VERSION 5.8 ;
BUSBITCHARS "[]" ;
DIVIDERCHAR "/" ;
UNITS
    DATABASE MICRONS 1000 ;
END UNITS

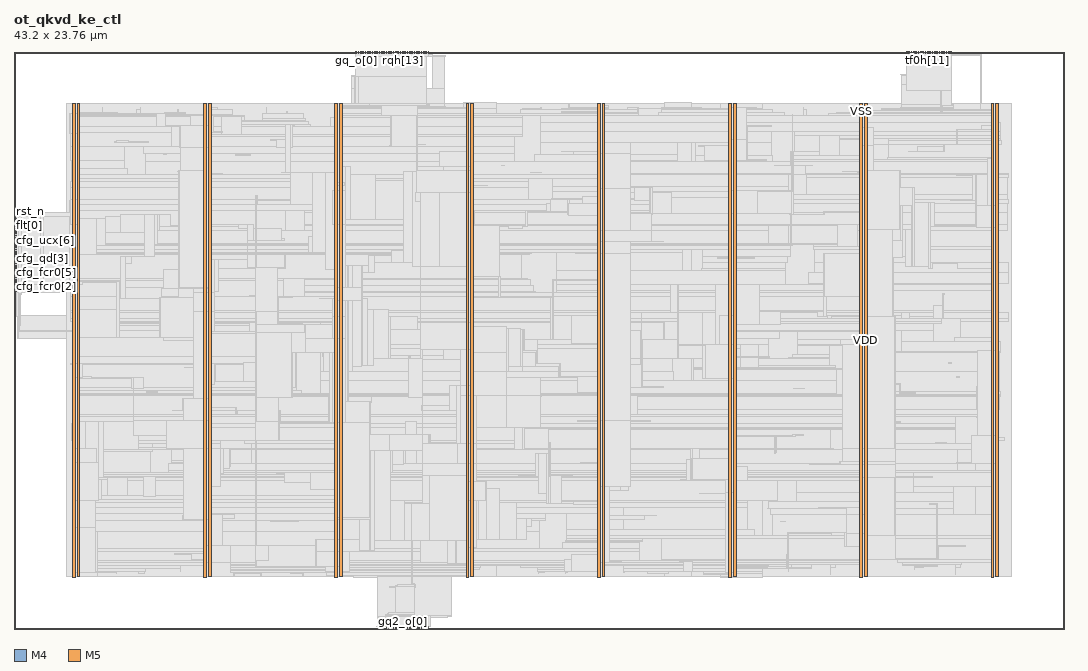
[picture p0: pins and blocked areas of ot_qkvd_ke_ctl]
MACRO ot_qkvd_ke_ctl
  FOREIGN ot_qkvd_ke_ctl 0 0 ;
  CLASS BLOCK ;
  SIZE 43.2 BY 23.76 ;
  PIN cfg_fcr0[0]
    DIRECTION INPUT ;
    USE SIGNAL ;
    PORT
      LAYER M4 ;
        RECT  0 13.872 0.084 13.896 ;
    END
  END cfg_fcr0[0]
  PIN cfg_fcr0[1]
    DIRECTION INPUT ;
    USE SIGNAL ;
    PORT
      LAYER M4 ;
        RECT  0 13.968 0.084 13.992 ;
    END
  END cfg_fcr0[1]
  PIN cfg_fcr0[2]
    DIRECTION INPUT ;
    USE SIGNAL ;
    PORT
      LAYER M4 ;
        RECT  0 14.064 0.084 14.088 ;
    END
  END cfg_fcr0[2]
  PIN cfg_fcr0[3]
    DIRECTION INPUT ;
    USE SIGNAL ;
    PORT
      LAYER M4 ;
        RECT  0 14.16 0.084 14.184 ;
    END
  END cfg_fcr0[3]
  PIN cfg_fcr0[4]
    DIRECTION INPUT ;
    USE SIGNAL ;
    PORT
      LAYER M4 ;
        RECT  0 14.256 0.084 14.28 ;
    END
  END cfg_fcr0[4]
  PIN cfg_fcr0[5]
    DIRECTION INPUT ;
    USE SIGNAL ;
    PORT
      LAYER M4 ;
        RECT  0 14.352 0.084 14.376 ;
    END
  END cfg_fcr0[5]
  PIN cfg_fcr0[6]
    DIRECTION INPUT ;
    USE SIGNAL ;
    PORT
      LAYER M4 ;
        RECT  0 14.448 0.084 14.472 ;
    END
  END cfg_fcr0[6]
  PIN cfg_fcr0[7]
    DIRECTION INPUT ;
    USE SIGNAL ;
    PORT
      LAYER M4 ;
        RECT  0 14.544 0.084 14.568 ;
    END
  END cfg_fcr0[7]
  PIN cfg_qd[0]
    DIRECTION INPUT ;
    USE SIGNAL ;
    PORT
      LAYER M4 ;
        RECT  0 14.64 0.084 14.664 ;
    END
  END cfg_qd[0]
  PIN cfg_qd[1]
    DIRECTION INPUT ;
    USE SIGNAL ;
    PORT
      LAYER M4 ;
        RECT  0 14.736 0.084 14.76 ;
    END
  END cfg_qd[1]
  PIN cfg_qd[2]
    DIRECTION INPUT ;
    USE SIGNAL ;
    PORT
      LAYER M4 ;
        RECT  0 14.832 0.084 14.856 ;
    END
  END cfg_qd[2]
  PIN cfg_qd[3]
    DIRECTION INPUT ;
    USE SIGNAL ;
    PORT
      LAYER M4 ;
        RECT  0 14.928 0.084 14.952 ;
    END
  END cfg_qd[3]
  PIN cfg_qd[4]
    DIRECTION INPUT ;
    USE SIGNAL ;
    PORT
      LAYER M4 ;
        RECT  0 15.024 0.084 15.048 ;
    END
  END cfg_qd[4]
  PIN cfg_qd[5]
    DIRECTION INPUT ;
    USE SIGNAL ;
    PORT
      LAYER M4 ;
        RECT  0 15.12 0.084 15.144 ;
    END
  END cfg_qd[5]
  PIN cfg_qd[6]
    DIRECTION INPUT ;
    USE SIGNAL ;
    PORT
      LAYER M4 ;
        RECT  0 15.216 0.084 15.24 ;
    END
  END cfg_qd[6]
  PIN cfg_qd[7]
    DIRECTION INPUT ;
    USE SIGNAL ;
    PORT
      LAYER M4 ;
        RECT  0 15.312 0.084 15.336 ;
    END
  END cfg_qd[7]
  PIN cfg_ucx[0]
    DIRECTION INPUT ;
    USE SIGNAL ;
    PORT
      LAYER M4 ;
        RECT  0 15.408 0.084 15.432 ;
    END
  END cfg_ucx[0]
  PIN cfg_ucx[1]
    DIRECTION INPUT ;
    USE SIGNAL ;
    PORT
      LAYER M4 ;
        RECT  0 15.504 0.084 15.528 ;
    END
  END cfg_ucx[1]
  PIN cfg_ucx[2]
    DIRECTION INPUT ;
    USE SIGNAL ;
    PORT
      LAYER M4 ;
        RECT  0 15.6 0.084 15.624 ;
    END
  END cfg_ucx[2]
  PIN cfg_ucx[3]
    DIRECTION INPUT ;
    USE SIGNAL ;
    PORT
      LAYER M4 ;
        RECT  0 15.696 0.084 15.72 ;
    END
  END cfg_ucx[3]
  PIN cfg_ucx[4]
    DIRECTION INPUT ;
    USE SIGNAL ;
    PORT
      LAYER M4 ;
        RECT  0 15.792 0.084 15.816 ;
    END
  END cfg_ucx[4]
  PIN cfg_ucx[5]
    DIRECTION INPUT ;
    USE SIGNAL ;
    PORT
      LAYER M4 ;
        RECT  0 15.888 0.084 15.912 ;
    END
  END cfg_ucx[5]
  PIN cfg_ucx[6]
    DIRECTION INPUT ;
    USE SIGNAL ;
    PORT
      LAYER M4 ;
        RECT  0 15.984 0.084 16.008 ;
    END
  END cfg_ucx[6]
  PIN cfg_ucx[7]
    DIRECTION INPUT ;
    USE SIGNAL ;
    PORT
      LAYER M4 ;
        RECT  0 16.08 0.084 16.104 ;
    END
  END cfg_ucx[7]
  PIN civ[0]
    DIRECTION INPUT ;
    USE SIGNAL ;
    PORT
      LAYER M5 ;
        RECT  15.312 0 15.336 0.084 ;
    END
  END civ[0]
  PIN civ[1]
    DIRECTION INPUT ;
    USE SIGNAL ;
    PORT
      LAYER M5 ;
        RECT  15.408 0 15.432 0.084 ;
    END
  END civ[1]
  PIN civ[2]
    DIRECTION INPUT ;
    USE SIGNAL ;
    PORT
      LAYER M5 ;
        RECT  15.504 0 15.528 0.084 ;
    END
  END civ[2]
  PIN clk
    DIRECTION INPUT ;
    USE SIGNAL ;
    PORT
      LAYER M4 ;
        RECT  0 16.176 0.084 16.2 ;
    END
  END clk
  PIN crq[0]
    DIRECTION INPUT ;
    USE SIGNAL ;
    PORT
      LAYER M5 ;
        RECT  15.6 0 15.624 0.084 ;
    END
  END crq[0]
  PIN crq[1]
    DIRECTION INPUT ;
    USE SIGNAL ;
    PORT
      LAYER M5 ;
        RECT  15.696 0 15.72 0.084 ;
    END
  END crq[1]
  PIN crq[2]
    DIRECTION INPUT ;
    USE SIGNAL ;
    PORT
      LAYER M5 ;
        RECT  15.792 0 15.816 0.084 ;
    END
  END crq[2]
  PIN crq[3]
    DIRECTION INPUT ;
    USE SIGNAL ;
    PORT
      LAYER M5 ;
        RECT  15.888 0 15.912 0.084 ;
    END
  END crq[3]
  PIN flt[0]
    DIRECTION OUTPUT ;
    USE SIGNAL ;
    PORT
      LAYER M4 ;
        RECT  0 16.272 0.084 16.296 ;
    END
  END flt[0]
  PIN flt[1]
    DIRECTION OUTPUT ;
    USE SIGNAL ;
    PORT
      LAYER M4 ;
        RECT  0 16.368 0.084 16.392 ;
    END
  END flt[1]
  PIN flt[2]
    DIRECTION OUTPUT ;
    USE SIGNAL ;
    PORT
      LAYER M4 ;
        RECT  0 16.464 0.084 16.488 ;
    END
  END flt[2]
  PIN flt[3]
    DIRECTION OUTPUT ;
    USE SIGNAL ;
    PORT
      LAYER M4 ;
        RECT  0 16.56 0.084 16.584 ;
    END
  END flt[3]
  PIN flt[4]
    DIRECTION OUTPUT ;
    USE SIGNAL ;
    PORT
      LAYER M4 ;
        RECT  0 16.656 0.084 16.68 ;
    END
  END flt[4]
  PIN flt[5]
    DIRECTION OUTPUT ;
    USE SIGNAL ;
    PORT
      LAYER M4 ;
        RECT  0 16.752 0.084 16.776 ;
    END
  END flt[5]
  PIN gq2_o[0]
    DIRECTION OUTPUT ;
    USE SIGNAL ;
    PORT
      LAYER M5 ;
        RECT  15.984 0 16.008 0.084 ;
    END
  END gq2_o[0]
  PIN gq2_o[1]
    DIRECTION OUTPUT ;
    USE SIGNAL ;
    PORT
      LAYER M5 ;
        RECT  16.08 0 16.104 0.084 ;
    END
  END gq2_o[1]
  PIN gq2_o[2]
    DIRECTION OUTPUT ;
    USE SIGNAL ;
    PORT
      LAYER M5 ;
        RECT  16.176 0 16.2 0.084 ;
    END
  END gq2_o[2]
  PIN gq_o[0]
    DIRECTION OUTPUT ;
    USE SIGNAL ;
    PORT
      LAYER M5 ;
        RECT  14.064 23.676 14.088 23.76 ;
    END
  END gq_o[0]
  PIN gq_o[1]
    DIRECTION OUTPUT ;
    USE SIGNAL ;
    PORT
      LAYER M5 ;
        RECT  14.16 23.676 14.184 23.76 ;
    END
  END gq_o[1]
  PIN gq_o[2]
    DIRECTION OUTPUT ;
    USE SIGNAL ;
    PORT
      LAYER M5 ;
        RECT  14.256 23.676 14.28 23.76 ;
    END
  END gq_o[2]
  PIN pp_r[0]
    DIRECTION OUTPUT ;
    USE SIGNAL ;
    PORT
      LAYER M5 ;
        RECT  14.352 23.676 14.376 23.76 ;
    END
  END pp_r[0]
  PIN pp_r[1]
    DIRECTION OUTPUT ;
    USE SIGNAL ;
    PORT
      LAYER M5 ;
        RECT  14.448 23.676 14.472 23.76 ;
    END
  END pp_r[1]
  PIN pp_r[2]
    DIRECTION OUTPUT ;
    USE SIGNAL ;
    PORT
      LAYER M5 ;
        RECT  14.544 23.676 14.568 23.76 ;
    END
  END pp_r[2]
  PIN pp_r[3]
    DIRECTION OUTPUT ;
    USE SIGNAL ;
    PORT
      LAYER M5 ;
        RECT  14.64 23.676 14.664 23.76 ;
    END
  END pp_r[3]
  PIN pp_t[0]
    DIRECTION OUTPUT ;
    USE SIGNAL ;
    PORT
      LAYER M5 ;
        RECT  16.272 0 16.296 0.084 ;
    END
  END pp_t[0]
  PIN pp_t[1]
    DIRECTION OUTPUT ;
    USE SIGNAL ;
    PORT
      LAYER M5 ;
        RECT  16.368 0 16.392 0.084 ;
    END
  END pp_t[1]
  PIN pp_t[2]
    DIRECTION OUTPUT ;
    USE SIGNAL ;
    PORT
      LAYER M5 ;
        RECT  16.464 0 16.488 0.084 ;
    END
  END pp_t[2]
  PIN rqh[0]
    DIRECTION INPUT ;
    USE SIGNAL ;
    PORT
      LAYER M5 ;
        RECT  14.736 23.676 14.76 23.76 ;
    END
  END rqh[0]
  PIN rqh[10]
    DIRECTION INPUT ;
    USE SIGNAL ;
    PORT
      LAYER M5 ;
        RECT  15.696 23.676 15.72 23.76 ;
    END
  END rqh[10]
  PIN rqh[11]
    DIRECTION INPUT ;
    USE SIGNAL ;
    PORT
      LAYER M5 ;
        RECT  15.792 23.676 15.816 23.76 ;
    END
  END rqh[11]
  PIN rqh[12]
    DIRECTION INPUT ;
    USE SIGNAL ;
    PORT
      LAYER M5 ;
        RECT  15.888 23.676 15.912 23.76 ;
    END
  END rqh[12]
  PIN rqh[13]
    DIRECTION INPUT ;
    USE SIGNAL ;
    PORT
      LAYER M5 ;
        RECT  15.984 23.676 16.008 23.76 ;
    END
  END rqh[13]
  PIN rqh[14]
    DIRECTION INPUT ;
    USE SIGNAL ;
    PORT
      LAYER M5 ;
        RECT  16.08 23.676 16.104 23.76 ;
    END
  END rqh[14]
  PIN rqh[15]
    DIRECTION INPUT ;
    USE SIGNAL ;
    PORT
      LAYER M5 ;
        RECT  16.176 23.676 16.2 23.76 ;
    END
  END rqh[15]
  PIN rqh[16]
    DIRECTION INPUT ;
    USE SIGNAL ;
    PORT
      LAYER M5 ;
        RECT  16.272 23.676 16.296 23.76 ;
    END
  END rqh[16]
  PIN rqh[17]
    DIRECTION INPUT ;
    USE SIGNAL ;
    PORT
      LAYER M5 ;
        RECT  16.368 23.676 16.392 23.76 ;
    END
  END rqh[17]
  PIN rqh[18]
    DIRECTION INPUT ;
    USE SIGNAL ;
    PORT
      LAYER M5 ;
        RECT  16.464 23.676 16.488 23.76 ;
    END
  END rqh[18]
  PIN rqh[19]
    DIRECTION INPUT ;
    USE SIGNAL ;
    PORT
      LAYER M5 ;
        RECT  16.56 23.676 16.584 23.76 ;
    END
  END rqh[19]
  PIN rqh[1]
    DIRECTION INPUT ;
    USE SIGNAL ;
    PORT
      LAYER M5 ;
        RECT  14.832 23.676 14.856 23.76 ;
    END
  END rqh[1]
  PIN rqh[2]
    DIRECTION INPUT ;
    USE SIGNAL ;
    PORT
      LAYER M5 ;
        RECT  14.928 23.676 14.952 23.76 ;
    END
  END rqh[2]
  PIN rqh[3]
    DIRECTION INPUT ;
    USE SIGNAL ;
    PORT
      LAYER M5 ;
        RECT  15.024 23.676 15.048 23.76 ;
    END
  END rqh[3]
  PIN rqh[4]
    DIRECTION INPUT ;
    USE SIGNAL ;
    PORT
      LAYER M5 ;
        RECT  15.12 23.676 15.144 23.76 ;
    END
  END rqh[4]
  PIN rqh[5]
    DIRECTION INPUT ;
    USE SIGNAL ;
    PORT
      LAYER M5 ;
        RECT  15.216 23.676 15.24 23.76 ;
    END
  END rqh[5]
  PIN rqh[6]
    DIRECTION INPUT ;
    USE SIGNAL ;
    PORT
      LAYER M5 ;
        RECT  15.312 23.676 15.336 23.76 ;
    END
  END rqh[6]
  PIN rqh[7]
    DIRECTION INPUT ;
    USE SIGNAL ;
    PORT
      LAYER M5 ;
        RECT  15.408 23.676 15.432 23.76 ;
    END
  END rqh[7]
  PIN rqh[8]
    DIRECTION INPUT ;
    USE SIGNAL ;
    PORT
      LAYER M5 ;
        RECT  15.504 23.676 15.528 23.76 ;
    END
  END rqh[8]
  PIN rqh[9]
    DIRECTION INPUT ;
    USE SIGNAL ;
    PORT
      LAYER M5 ;
        RECT  15.6 23.676 15.624 23.76 ;
    END
  END rqh[9]
  PIN rqq_o[0]
    DIRECTION OUTPUT ;
    USE SIGNAL ;
    PORT
      LAYER M5 ;
        RECT  16.56 0 16.584 0.084 ;
    END
  END rqq_o[0]
  PIN rqq_o[1]
    DIRECTION OUTPUT ;
    USE SIGNAL ;
    PORT
      LAYER M5 ;
        RECT  16.656 0 16.68 0.084 ;
    END
  END rqq_o[1]
  PIN rqq_o[2]
    DIRECTION OUTPUT ;
    USE SIGNAL ;
    PORT
      LAYER M5 ;
        RECT  16.752 0 16.776 0.084 ;
    END
  END rqq_o[2]
  PIN rqq_o[3]
    DIRECTION OUTPUT ;
    USE SIGNAL ;
    PORT
      LAYER M5 ;
        RECT  16.848 0 16.872 0.084 ;
    END
  END rqq_o[3]
  PIN rqv
    DIRECTION INPUT ;
    USE SIGNAL ;
    PORT
      LAYER M5 ;
        RECT  16.656 23.676 16.68 23.76 ;
    END
  END rqv
  PIN rs_n
    DIRECTION OUTPUT ;
    USE SIGNAL ;
    PORT
      LAYER M5 ;
        RECT  16.752 23.676 16.776 23.76 ;
    END
  END rs_n
  PIN rs_s
    DIRECTION OUTPUT ;
    USE SIGNAL ;
    PORT
      LAYER M5 ;
        RECT  16.944 0 16.968 0.084 ;
    END
  END rs_s
  PIN rs_ta
    DIRECTION OUTPUT ;
    USE SIGNAL ;
    PORT
      LAYER M5 ;
        RECT  17.04 0 17.064 0.084 ;
    END
  END rs_ta
  PIN rs_tb
    DIRECTION OUTPUT ;
    USE SIGNAL ;
    PORT
      LAYER M5 ;
        RECT  16.848 23.676 16.872 23.76 ;
    END
  END rs_tb
  PIN rst_n
    DIRECTION INPUT ;
    USE SIGNAL ;
    PORT
      LAYER M4 ;
        RECT  0 16.848 0.084 16.872 ;
    END
  END rst_n
  PIN tf0h[0]
    DIRECTION OUTPUT ;
    USE SIGNAL ;
    PORT
      LAYER M5 ;
        RECT  16.944 23.676 16.968 23.76 ;
    END
  END tf0h[0]
  PIN tf0h[10]
    DIRECTION OUTPUT ;
    USE SIGNAL ;
    PORT
      LAYER M5 ;
        RECT  37.488 23.676 37.512 23.76 ;
    END
  END tf0h[10]
  PIN tf0h[11]
    DIRECTION OUTPUT ;
    USE SIGNAL ;
    PORT
      LAYER M5 ;
        RECT  37.584 23.676 37.608 23.76 ;
    END
  END tf0h[11]
  PIN tf0h[12]
    DIRECTION OUTPUT ;
    USE SIGNAL ;
    PORT
      LAYER M5 ;
        RECT  37.68 23.676 37.704 23.76 ;
    END
  END tf0h[12]
  PIN tf0h[13]
    DIRECTION OUTPUT ;
    USE SIGNAL ;
    PORT
      LAYER M5 ;
        RECT  37.776 23.676 37.8 23.76 ;
    END
  END tf0h[13]
  PIN tf0h[14]
    DIRECTION OUTPUT ;
    USE SIGNAL ;
    PORT
      LAYER M5 ;
        RECT  37.872 23.676 37.896 23.76 ;
    END
  END tf0h[14]
  PIN tf0h[15]
    DIRECTION OUTPUT ;
    USE SIGNAL ;
    PORT
      LAYER M5 ;
        RECT  37.968 23.676 37.992 23.76 ;
    END
  END tf0h[15]
  PIN tf0h[16]
    DIRECTION OUTPUT ;
    USE SIGNAL ;
    PORT
      LAYER M5 ;
        RECT  38.064 23.676 38.088 23.76 ;
    END
  END tf0h[16]
  PIN tf0h[17]
    DIRECTION OUTPUT ;
    USE SIGNAL ;
    PORT
      LAYER M5 ;
        RECT  38.16 23.676 38.184 23.76 ;
    END
  END tf0h[17]
  PIN tf0h[18]
    DIRECTION OUTPUT ;
    USE SIGNAL ;
    PORT
      LAYER M5 ;
        RECT  38.256 23.676 38.28 23.76 ;
    END
  END tf0h[18]
  PIN tf0h[19]
    DIRECTION OUTPUT ;
    USE SIGNAL ;
    PORT
      LAYER M5 ;
        RECT  38.352 23.676 38.376 23.76 ;
    END
  END tf0h[19]
  PIN tf0h[1]
    DIRECTION OUTPUT ;
    USE SIGNAL ;
    PORT
      LAYER M5 ;
        RECT  17.04 23.676 17.064 23.76 ;
    END
  END tf0h[1]
  PIN tf0h[2]
    DIRECTION OUTPUT ;
    USE SIGNAL ;
    PORT
      LAYER M5 ;
        RECT  36.72 23.676 36.744 23.76 ;
    END
  END tf0h[2]
  PIN tf0h[3]
    DIRECTION OUTPUT ;
    USE SIGNAL ;
    PORT
      LAYER M5 ;
        RECT  36.816 23.676 36.84 23.76 ;
    END
  END tf0h[3]
  PIN tf0h[4]
    DIRECTION OUTPUT ;
    USE SIGNAL ;
    PORT
      LAYER M5 ;
        RECT  36.912 23.676 36.936 23.76 ;
    END
  END tf0h[4]
  PIN tf0h[5]
    DIRECTION OUTPUT ;
    USE SIGNAL ;
    PORT
      LAYER M5 ;
        RECT  37.008 23.676 37.032 23.76 ;
    END
  END tf0h[5]
  PIN tf0h[6]
    DIRECTION OUTPUT ;
    USE SIGNAL ;
    PORT
      LAYER M5 ;
        RECT  37.104 23.676 37.128 23.76 ;
    END
  END tf0h[6]
  PIN tf0h[7]
    DIRECTION OUTPUT ;
    USE SIGNAL ;
    PORT
      LAYER M5 ;
        RECT  37.2 23.676 37.224 23.76 ;
    END
  END tf0h[7]
  PIN tf0h[8]
    DIRECTION OUTPUT ;
    USE SIGNAL ;
    PORT
      LAYER M5 ;
        RECT  37.296 23.676 37.32 23.76 ;
    END
  END tf0h[8]
  PIN tf0h[9]
    DIRECTION OUTPUT ;
    USE SIGNAL ;
    PORT
      LAYER M5 ;
        RECT  37.392 23.676 37.416 23.76 ;
    END
  END tf0h[9]
  PIN tv0
    DIRECTION OUTPUT ;
    USE SIGNAL ;
    PORT
      LAYER M5 ;
        RECT  38.448 23.676 38.472 23.76 ;
    END
  END tv0
  PIN upq
    DIRECTION INPUT ;
    USE SIGNAL ;
    PORT
      LAYER M5 ;
        RECT  38.544 23.676 38.568 23.76 ;
    END
  END upq
  PIN VDD
    DIRECTION INOUT ;
    USE POWER ;
    PORT
      LAYER M5 ;
        RECT  40.392 2.151 40.512 21.609 ;
        RECT  34.992 2.151 35.112 21.609 ;
        RECT  29.592 2.151 29.712 21.609 ;
        RECT  24.192 2.151 24.312 21.609 ;
        RECT  18.792 2.151 18.912 21.609 ;
        RECT  13.392 2.151 13.512 21.609 ;
        RECT  7.992 2.151 8.112 21.609 ;
        RECT  2.592 2.151 2.712 21.609 ;
    END
  END VDD
  PIN VSS
    DIRECTION INOUT ;
    USE GROUND ;
    PORT
      LAYER M5 ;
        RECT  40.2 2.137 40.32 21.623 ;
        RECT  34.8 2.137 34.92 21.623 ;
        RECT  29.4 2.137 29.52 21.623 ;
        RECT  24 2.137 24.12 21.623 ;
        RECT  18.6 2.137 18.72 21.623 ;
        RECT  13.2 2.137 13.32 21.623 ;
        RECT  7.8 2.137 7.92 21.623 ;
        RECT  2.4 2.137 2.52 21.623 ;
    END
  END VSS
  # OT_OBS_CLOSED layer=M5 d_um=1.536 added=51
  OBS
    LAYER RVTN ;
     RECT  2.16 2.16 41.04 2.295 ;
     RECT  2.16 2.565 41.04 2.835 ;
     RECT  2.16 3.105 41.04 3.375 ;
     RECT  2.16 3.645 41.04 3.915 ;
     RECT  2.16 4.185 41.04 4.455 ;
     RECT  2.16 4.725 41.04 4.995 ;
     RECT  2.16 5.265 41.04 5.535 ;
     RECT  2.16 5.805 41.04 6.075 ;
     RECT  2.16 6.345 41.04 6.615 ;
     RECT  2.16 6.885 41.04 7.155 ;
     RECT  2.16 7.425 41.04 7.695 ;
     RECT  2.16 7.965 41.04 8.235 ;
     RECT  2.16 8.505 41.04 8.775 ;
     RECT  2.16 9.045 41.04 9.315 ;
     RECT  2.16 9.585 41.04 9.855 ;
     RECT  2.16 10.125 41.04 10.395 ;
     RECT  2.16 10.665 41.04 10.935 ;
     RECT  2.16 11.205 41.04 11.475 ;
     RECT  2.16 11.745 41.04 12.015 ;
     RECT  2.16 12.285 41.04 12.555 ;
     RECT  2.16 12.825 41.04 13.095 ;
     RECT  2.16 13.365 41.04 13.635 ;
     RECT  2.16 13.905 41.04 14.175 ;
     RECT  2.16 14.445 41.04 14.715 ;
     RECT  2.16 14.985 41.04 15.255 ;
     RECT  2.16 15.525 41.04 15.795 ;
     RECT  2.16 16.065 41.04 16.335 ;
     RECT  2.16 16.605 41.04 16.875 ;
     RECT  2.16 17.145 41.04 17.415 ;
     RECT  2.16 17.685 41.04 17.955 ;
     RECT  2.16 18.225 41.04 18.495 ;
     RECT  2.16 18.765 41.04 19.035 ;
     RECT  2.16 19.305 41.04 19.575 ;
     RECT  2.16 19.845 41.04 20.115 ;
     RECT  2.16 20.385 41.04 20.655 ;
     RECT  2.16 20.925 41.04 21.195 ;
     RECT  2.16 21.465 41.04 21.6 ;
    LAYER RVTP ;
     RECT  2.16 2.295 41.04 2.565 ;
     RECT  2.16 2.835 41.04 3.105 ;
     RECT  2.16 3.375 41.04 3.645 ;
     RECT  2.16 3.915 41.04 4.185 ;
     RECT  2.16 4.455 41.04 4.725 ;
     RECT  2.16 4.995 41.04 5.265 ;
     RECT  2.16 5.535 41.04 5.805 ;
     RECT  2.16 6.075 41.04 6.345 ;
     RECT  2.16 6.615 41.04 6.885 ;
     RECT  2.16 7.155 41.04 7.425 ;
     RECT  2.16 7.695 41.04 7.965 ;
     RECT  2.16 8.235 41.04 8.505 ;
     RECT  2.16 8.775 41.04 9.045 ;
     RECT  2.16 9.315 41.04 9.585 ;
     RECT  2.16 9.855 41.04 10.125 ;
     RECT  2.16 10.395 41.04 10.665 ;
     RECT  2.16 10.935 41.04 11.205 ;
     RECT  2.16 11.475 41.04 11.745 ;
     RECT  2.16 12.015 41.04 12.285 ;
     RECT  2.16 12.555 41.04 12.825 ;
     RECT  2.16 13.095 41.04 13.365 ;
     RECT  2.16 13.635 41.04 13.905 ;
     RECT  2.16 14.175 41.04 14.445 ;
     RECT  2.16 14.715 41.04 14.985 ;
     RECT  2.16 15.255 41.04 15.525 ;
     RECT  2.16 15.795 41.04 16.065 ;
     RECT  2.16 16.335 41.04 16.605 ;
     RECT  2.16 16.875 41.04 17.145 ;
     RECT  2.16 17.415 41.04 17.685 ;
     RECT  2.16 17.955 41.04 18.225 ;
     RECT  2.16 18.495 41.04 18.765 ;
     RECT  2.16 19.035 41.04 19.305 ;
     RECT  2.16 19.575 41.04 19.845 ;
     RECT  2.16 20.115 41.04 20.385 ;
     RECT  2.16 20.655 41.04 20.925 ;
     RECT  2.16 21.195 41.04 21.465 ;
    LAYER M1 ;
     RECT  2.16 2.151 41.04 21.609 ;
    LAYER M2 ;
     RECT  0.139 11.952 0.175 11.97 ;
     RECT  0.103 12.87 0.175 12.888 ;
     RECT  0.175 15.876 0.347 15.894 ;
     RECT  0.427 14.49 0.463 14.508 ;
     RECT  0.463 14.49 0.499 14.67 ;
     RECT  0.499 16.416 0.535 16.434 ;
     RECT  0.175 11.952 2.16 12.888 ;
     RECT  0.499 13.842 2.16 15.318 ;
     RECT  0.535 16.416 2.16 16.524 ;
     RECT  2.16 2.151 13.963 21.609 ;
     RECT  13.963 2.106 15.323 21.609 ;
     RECT  15.323 2.151 16.447 21.609 ;
     RECT  16.447 2.106 16.979 21.609 ;
     RECT  16.979 2.151 18.499 21.609 ;
     RECT  18.499 2.151 19.859 21.654 ;
     RECT  19.859 2.151 26.779 21.609 ;
     RECT  26.779 2.151 27.887 21.654 ;
     RECT  27.887 2.151 29.047 21.609 ;
     RECT  29.047 2.106 30.803 21.609 ;
     RECT  37.255 22.788 37.355 22.806 ;
     RECT  30.803 2.151 41.04 21.609 ;
    LAYER M3 ;
     RECT  14.94 0.091 14.958 0.475 ;
     RECT  16.128 0.091 17.118 0.475 ;
     RECT  14.94 0.475 17.838 0.523 ;
     RECT  13.968 2.101 13.986 2.143 ;
     RECT  14.94 0.523 17.982 2.143 ;
     RECT  29.052 2.101 29.07 2.143 ;
     RECT  13.215 2.143 13.986 2.191 ;
     RECT  14.94 2.143 18.705 2.191 ;
     RECT  29.052 2.143 29.505 2.227 ;
     RECT  11.88 2.191 11.898 2.263 ;
     RECT  5.364 2.263 5.382 2.299 ;
     RECT  9.036 2.191 9.054 2.299 ;
     RECT  10.152 2.191 10.17 2.299 ;
     RECT  28.368 2.227 29.505 2.299 ;
     RECT  30.78 2.101 30.798 2.299 ;
     RECT  3.42 2.191 3.438 2.335 ;
     RECT  4.212 2.299 4.23 2.335 ;
     RECT  9.036 2.299 10.17 2.335 ;
     RECT  11.376 2.263 11.898 2.335 ;
     RECT  12.852 2.191 18.705 2.335 ;
     RECT  21.564 2.263 21.582 2.335 ;
     RECT  22.68 2.299 22.698 2.335 ;
     RECT  3.276 2.335 4.23 2.347 ;
     RECT  5.112 2.299 5.382 2.347 ;
     RECT  24.015 2.143 24.105 2.347 ;
     RECT  26.064 2.299 26.946 2.347 ;
     RECT  3.276 2.347 5.382 2.371 ;
     RECT  21.564 2.335 21.834 2.371 ;
     RECT  22.68 2.335 22.77 2.371 ;
     RECT  25.092 2.335 25.11 2.371 ;
     RECT  26.064 2.347 27.594 2.371 ;
     RECT  28.368 2.299 30.798 2.371 ;
     RECT  3.276 2.371 5.418 2.381 ;
     RECT  2.415 2.143 2.505 2.413 ;
     RECT  7.815 2.143 7.905 2.413 ;
     RECT  8.892 2.335 18.705 2.413 ;
     RECT  23.94 2.347 24.105 2.413 ;
     RECT  34.815 2.143 34.905 2.413 ;
     RECT  40.215 2.143 40.305 2.413 ;
     RECT  8.892 2.413 18.897 2.461 ;
     RECT  21.528 2.371 23.13 2.461 ;
     RECT  23.94 2.413 24.297 2.461 ;
     RECT  25.092 2.371 30.798 2.491 ;
     RECT  3.42 2.381 5.418 2.497 ;
     RECT  6.84 2.371 6.858 2.497 ;
     RECT  8.892 2.461 19.134 2.533 ;
     RECT  21.528 2.461 24.297 2.533 ;
     RECT  31.86 2.371 31.878 2.533 ;
     RECT  33.588 2.227 33.606 2.533 ;
     RECT  37.044 2.461 37.062 2.533 ;
     RECT  38.736 2.227 38.754 2.533 ;
     RECT  37.044 2.533 37.422 2.569 ;
     RECT  3.42 2.497 6.858 2.605 ;
     RECT  7.815 2.413 8.097 2.605 ;
     RECT  8.892 2.533 19.206 2.605 ;
     RECT  20.844 2.533 24.297 2.605 ;
     RECT  25.092 2.491 31.05 2.605 ;
     RECT  37.044 2.569 37.998 2.605 ;
     RECT  8.892 2.605 31.05 2.641 ;
     RECT  31.86 2.533 31.986 2.641 ;
     RECT  32.796 2.488 32.814 2.641 ;
     RECT  33.588 2.533 33.786 2.641 ;
     RECT  34.815 2.413 35.097 2.641 ;
     RECT  36.54 2.605 37.998 2.641 ;
     RECT  38.736 2.533 38.934 2.641 ;
     RECT  3.42 2.605 8.097 2.731 ;
     RECT  8.892 2.641 35.097 2.731 ;
     RECT  36.54 2.641 38.97 2.731 ;
     RECT  40.215 2.413 40.497 2.731 ;
     RECT  3.42 2.731 35.097 2.831 ;
     RECT  36.36 2.731 40.497 2.839 ;
     RECT  26.64 2.831 35.097 2.869 ;
     RECT  36.324 2.839 40.497 2.869 ;
     RECT  3.42 2.831 25.722 3.209 ;
     RECT  3.456 3.209 25.722 3.299 ;
     RECT  22.572 3.299 25.722 3.569 ;
     RECT  22.68 3.569 25.722 3.613 ;
     RECT  22.68 3.613 25.866 3.641 ;
     RECT  22.752 3.641 25.866 3.721 ;
     RECT  26.64 2.869 40.497 3.721 ;
     RECT  22.752 3.721 40.497 3.839 ;
     RECT  2.415 2.413 2.697 3.991 ;
     RECT  3.456 3.299 21.618 3.991 ;
     RECT  22.752 3.839 30.474 4.109 ;
     RECT  2.415 3.991 21.618 4.459 ;
     RECT  31.212 3.839 40.497 4.693 ;
     RECT  31.14 4.693 40.497 4.721 ;
     RECT  2.415 4.459 21.87 4.765 ;
     RECT  22.752 4.109 24.297 4.765 ;
     RECT  31.14 4.721 38.646 4.939 ;
     RECT  2.415 4.765 24.297 4.999 ;
     RECT  25.056 4.109 30.186 4.999 ;
     RECT  2.415 4.999 30.186 5.225 ;
     RECT  31.032 4.939 38.646 5.261 ;
     RECT  14.22 5.225 30.186 5.305 ;
     RECT  31.032 5.261 31.41 5.305 ;
     RECT  2.415 5.225 13.497 5.309 ;
     RECT  3.6 5.309 13.497 5.495 ;
     RECT  32.184 5.261 38.646 5.603 ;
     RECT  37.008 5.603 38.646 5.881 ;
     RECT  39.564 4.721 40.497 5.881 ;
     RECT  4.68 5.495 13.497 6.115 ;
     RECT  14.22 5.305 31.41 6.115 ;
     RECT  32.184 5.603 36.198 6.115 ;
     RECT  2.415 5.309 2.697 6.151 ;
     RECT  3.6 5.495 3.834 6.151 ;
     RECT  2.415 6.151 3.834 6.241 ;
     RECT  4.68 6.115 36.198 6.241 ;
     RECT  2.415 6.241 36.198 6.277 ;
     RECT  2.412 6.277 36.198 6.365 ;
     RECT  2.415 6.365 36.198 6.421 ;
     RECT  37.008 5.881 40.497 6.421 ;
     RECT  2.415 6.421 40.497 6.449 ;
     RECT  6.372 6.449 40.497 6.539 ;
     RECT  6.372 6.539 38.826 6.809 ;
     RECT  6.48 6.809 8.766 6.845 ;
     RECT  6.48 6.845 8.55 6.917 ;
     RECT  2.415 6.449 5.634 7.321 ;
     RECT  9.792 6.809 38.826 7.385 ;
     RECT  34.488 7.385 38.826 7.393 ;
     RECT  39.564 6.539 40.497 7.393 ;
     RECT  9.792 7.385 33.714 7.421 ;
     RECT  2.415 7.321 5.706 7.427 ;
     RECT  9.792 7.421 21.006 7.427 ;
     RECT  34.488 7.393 40.497 7.619 ;
     RECT  5.04 7.427 5.706 7.627 ;
     RECT  6.48 6.917 8.514 7.627 ;
     RECT  9.792 7.427 20.934 7.627 ;
     RECT  5.04 7.627 8.514 7.735 ;
     RECT  9.504 7.627 20.934 7.735 ;
     RECT  39.456 7.619 40.497 7.735 ;
     RECT  2.415 7.427 4.23 7.771 ;
     RECT  39.456 7.735 40.734 7.889 ;
     RECT  39.456 7.889 40.497 7.949 ;
     RECT  21.996 7.421 33.606 8.203 ;
     RECT  34.488 7.619 38.718 8.203 ;
     RECT  21.996 8.203 38.718 8.239 ;
     RECT  5.04 7.735 20.934 8.275 ;
     RECT  21.708 8.239 38.718 8.275 ;
     RECT  2.376 7.771 4.23 8.465 ;
     RECT  2.415 8.465 4.23 8.473 ;
     RECT  5.04 8.275 38.718 8.473 ;
     RECT  39.924 7.949 40.497 8.707 ;
     RECT  2.415 8.473 38.718 8.743 ;
     RECT  39.6 8.707 40.497 8.743 ;
     RECT  2.415 8.743 40.497 8.807 ;
     RECT  25.452 8.807 40.497 8.843 ;
     RECT  25.668 8.843 40.497 9.013 ;
     RECT  25.668 9.013 40.554 9.553 ;
     RECT  2.415 8.807 24.498 9.625 ;
     RECT  25.668 9.553 40.59 9.625 ;
     RECT  2.415 9.625 40.59 9.629 ;
     RECT  2.415 9.629 33.822 9.689 ;
     RECT  34.812 9.629 40.59 9.779 ;
     RECT  2.415 9.689 11.826 9.815 ;
     RECT  2.415 9.815 11.61 9.923 ;
     RECT  12.6 9.689 33.822 10.229 ;
     RECT  12.6 10.229 27.126 10.589 ;
     RECT  34.812 9.779 40.554 10.589 ;
     RECT  27.936 10.229 33.822 10.669 ;
     RECT  34.812 10.589 35.097 10.669 ;
     RECT  27.936 10.669 35.097 10.733 ;
     RECT  27.936 10.733 33.786 10.769 ;
     RECT  30.636 10.769 33.786 10.859 ;
     RECT  2.415 9.923 10.818 10.891 ;
     RECT  2.34 10.891 10.818 10.931 ;
     RECT  30.636 10.859 33.57 11.129 ;
     RECT  31.86 11.129 33.57 11.165 ;
     RECT  2.415 10.931 10.818 11.213 ;
     RECT  30.636 11.129 31.086 11.213 ;
     RECT  32.04 11.165 33.57 11.309 ;
     RECT  35.82 10.589 40.554 11.371 ;
     RECT  35.82 11.371 40.59 11.435 ;
     RECT  12.6 10.589 27.09 11.551 ;
     RECT  27.936 10.769 29.898 11.551 ;
     RECT  32.22 11.309 33.57 11.659 ;
     RECT  12.6 11.551 29.898 11.705 ;
     RECT  27.468 11.705 29.898 11.713 ;
     RECT  30.636 11.213 31.05 11.713 ;
     RECT  34.815 10.733 35.097 11.713 ;
     RECT  36.504 11.435 40.59 11.813 ;
     RECT  34.776 11.713 35.097 11.821 ;
     RECT  32.22 11.659 34.002 11.911 ;
     RECT  34.776 11.821 35.766 11.911 ;
     RECT  27.468 11.713 31.05 11.947 ;
     RECT  38.7 11.813 40.497 11.975 ;
     RECT  11.592 9.923 11.61 12.091 ;
     RECT  2.415 11.213 10.782 12.139 ;
     RECT  11.592 12.091 11.646 12.139 ;
     RECT  27.468 11.947 31.482 12.253 ;
     RECT  32.22 11.911 35.766 12.253 ;
     RECT  27.468 12.253 35.766 12.289 ;
     RECT  36.504 11.813 37.818 12.289 ;
     RECT  0.144 11.947 0.162 12.325 ;
     RECT  2.415 12.139 10.854 12.475 ;
     RECT  11.592 12.139 11.754 12.475 ;
     RECT  0.144 12.325 0.198 12.487 ;
     RECT  2.415 12.475 11.754 12.559 ;
     RECT  27.468 12.289 37.818 12.559 ;
     RECT  2.415 12.559 11.862 12.595 ;
     RECT  12.6 11.705 26.73 12.595 ;
     RECT  2.415 12.595 26.73 12.631 ;
     RECT  27.468 12.559 38.142 12.631 ;
     RECT  38.952 11.975 40.497 12.631 ;
     RECT  2.34 12.631 38.142 12.757 ;
     RECT  38.952 12.631 40.914 12.757 ;
     RECT  0.144 12.487 0.27 12.865 ;
     RECT  2.34 12.757 40.914 13.019 ;
     RECT  2.34 13.019 40.497 13.091 ;
     RECT  2.34 13.091 35.097 13.661 ;
     RECT  11.952 13.661 35.097 13.829 ;
     RECT  0.108 12.865 0.27 13.837 ;
     RECT  0.108 13.837 0.522 13.901 ;
     RECT  11.952 13.829 21.474 13.901 ;
     RECT  0.144 13.901 0.522 13.945 ;
     RECT  22.32 13.829 35.097 13.945 ;
     RECT  35.928 13.091 40.497 13.945 ;
     RECT  0.144 13.945 0.558 13.997 ;
     RECT  0.18 13.997 0.558 14.093 ;
     RECT  11.952 13.901 21.366 14.135 ;
     RECT  22.32 13.945 40.497 14.189 ;
     RECT  32.688 14.189 40.497 14.215 ;
     RECT  2.34 13.661 11.106 14.347 ;
     RECT  11.952 14.135 21.258 14.369 ;
     RECT  2.304 14.347 11.106 14.413 ;
     RECT  11.952 14.369 21.114 14.413 ;
     RECT  2.304 14.413 21.114 14.441 ;
     RECT  32.688 14.215 40.914 14.675 ;
     RECT  22.32 14.189 31.734 14.747 ;
     RECT  28.296 14.747 31.734 14.819 ;
     RECT  0.252 14.093 0.558 14.861 ;
     RECT  28.332 14.819 31.734 15.061 ;
     RECT  32.94 14.675 40.914 15.089 ;
     RECT  28.332 15.061 31.842 15.331 ;
     RECT  2.304 14.441 20.862 15.421 ;
     RECT  2.304 15.421 21.222 15.457 ;
     RECT  2.304 15.457 21.294 15.493 ;
     RECT  22.32 14.747 27.522 15.493 ;
     RECT  0.432 14.861 0.558 15.499 ;
     RECT  2.304 15.493 27.522 15.601 ;
     RECT  28.332 15.331 31.95 15.601 ;
     RECT  32.94 15.089 40.497 15.601 ;
     RECT  0.432 15.499 0.63 15.629 ;
     RECT  32.904 15.601 40.497 15.755 ;
     RECT  0.324 15.691 0.342 15.787 ;
     RECT  2.304 15.601 31.95 15.787 ;
     RECT  2.304 15.787 31.986 15.799 ;
     RECT  32.904 15.755 33.894 15.799 ;
     RECT  2.304 15.799 33.894 15.863 ;
     RECT  0.18 15.787 0.342 15.899 ;
     RECT  0.324 15.899 0.342 15.917 ;
     RECT  2.304 15.863 31.05 16.375 ;
     RECT  2.268 16.375 31.05 16.403 ;
     RECT  34.704 15.755 40.497 16.411 ;
     RECT  0.504 16.411 0.522 16.501 ;
     RECT  11.952 16.403 31.05 16.609 ;
     RECT  31.86 15.863 33.894 16.609 ;
     RECT  11.952 16.609 33.894 16.645 ;
     RECT  34.704 16.411 40.878 16.645 ;
     RECT  0.504 16.501 0.558 16.685 ;
     RECT  0.324 16.747 0.342 16.843 ;
     RECT  0.108 16.843 0.342 16.877 ;
     RECT  0.108 16.877 0.126 16.973 ;
     RECT  1.116 16.939 1.134 17.117 ;
     RECT  11.952 16.645 40.878 17.117 ;
     RECT  2.268 16.403 11.178 17.221 ;
     RECT  11.952 17.117 30.222 17.221 ;
     RECT  2.268 17.221 30.222 17.447 ;
     RECT  30.96 17.117 40.878 17.491 ;
     RECT  2.304 17.447 30.222 17.681 ;
     RECT  30.96 17.491 40.914 17.681 ;
     RECT  22.104 17.681 30.222 17.693 ;
     RECT  30.96 17.681 40.878 17.879 ;
     RECT  22.176 17.693 30.222 17.995 ;
     RECT  30.96 17.879 31.878 17.995 ;
     RECT  2.304 17.681 21.15 18.185 ;
     RECT  22.176 17.995 31.878 18.221 ;
     RECT  2.34 18.185 21.15 18.419 ;
     RECT  2.376 18.419 21.15 18.535 ;
     RECT  22.176 18.221 24.426 18.535 ;
     RECT  32.616 17.879 40.878 18.571 ;
     RECT  2.376 18.535 24.426 18.689 ;
     RECT  25.2 18.221 31.878 18.697 ;
     RECT  32.616 18.571 40.914 18.697 ;
     RECT  25.2 18.697 40.914 18.761 ;
     RECT  2.376 18.689 4.662 18.959 ;
     RECT  5.4 18.689 24.318 19.229 ;
     RECT  25.2 18.761 40.497 19.229 ;
     RECT  2.376 18.959 4.554 19.273 ;
     RECT  25.2 19.229 27.306 19.273 ;
     RECT  32.004 19.229 40.497 19.301 ;
     RECT  35.928 19.301 40.497 19.409 ;
     RECT  28.044 19.229 31.194 19.499 ;
     RECT  32.004 19.301 35.097 19.499 ;
     RECT  21.42 19.229 24.318 19.531 ;
     RECT  25.092 19.273 27.306 19.531 ;
     RECT  21.42 19.531 27.306 19.535 ;
     RECT  5.4 19.229 20.61 19.579 ;
     RECT  32.004 19.499 33.138 19.661 ;
     RECT  2.34 19.273 4.554 19.849 ;
     RECT  5.328 19.579 20.61 19.849 ;
     RECT  2.34 19.849 20.61 19.853 ;
     RECT  35.964 19.409 40.497 19.921 ;
     RECT  21.672 19.535 27.306 20.011 ;
     RECT  28.044 19.499 31.158 20.011 ;
     RECT  35.964 19.921 40.626 20.111 ;
     RECT  33.948 19.499 35.097 20.119 ;
     RECT  33.948 20.119 35.19 20.191 ;
     RECT  35.964 20.111 40.59 20.191 ;
     RECT  7.74 19.853 20.61 20.281 ;
     RECT  32.112 19.661 33.138 20.317 ;
     RECT  33.948 20.191 40.59 20.317 ;
     RECT  7.74 20.281 20.934 20.345 ;
     RECT  2.34 19.853 6.462 20.429 ;
     RECT  21.672 20.011 31.158 20.461 ;
     RECT  32.112 20.317 40.59 20.461 ;
     RECT  2.415 20.429 6.462 20.659 ;
     RECT  2.415 20.659 6.75 20.672 ;
     RECT  7.74 20.345 8.55 20.672 ;
     RECT  9.36 20.345 20.934 20.687 ;
     RECT  9.36 20.687 12.186 20.759 ;
     RECT  21.672 20.461 40.59 20.849 ;
     RECT  9.36 20.759 12.114 20.885 ;
     RECT  9.36 20.885 12.006 20.921 ;
     RECT  10.224 20.921 12.006 20.993 ;
     RECT  13.032 20.687 20.934 21.029 ;
     RECT  2.415 20.672 8.55 21.091 ;
     RECT  9.36 20.921 9.486 21.091 ;
     RECT  2.415 21.091 9.486 21.119 ;
     RECT  13.176 21.029 20.934 21.119 ;
     RECT  21.672 20.849 40.497 21.119 ;
     RECT  13.215 21.119 20.934 21.127 ;
     RECT  21.672 21.119 25.686 21.127 ;
     RECT  5.04 21.119 8.982 21.149 ;
     RECT  10.224 20.993 11.898 21.191 ;
     RECT  13.215 21.127 25.686 21.191 ;
     RECT  33.516 21.119 40.497 21.191 ;
     RECT  5.04 21.149 7.038 21.197 ;
     RECT  10.368 21.191 11.898 21.227 ;
     RECT  2.415 21.119 4.266 21.263 ;
     RECT  6.192 21.197 7.038 21.263 ;
     RECT  26.532 21.119 31.698 21.263 ;
     RECT  33.84 21.191 40.497 21.263 ;
     RECT  11.232 21.227 11.25 21.299 ;
     RECT  2.415 21.263 2.697 21.347 ;
     RECT  34.524 21.263 40.497 21.347 ;
     RECT  5.04 21.197 5.202 21.389 ;
     RECT  6.732 21.263 6.75 21.389 ;
     RECT  7.815 21.149 8.982 21.389 ;
     RECT  20.844 21.191 25.686 21.389 ;
     RECT  26.64 21.263 31.194 21.389 ;
     RECT  32.472 21.119 32.598 21.389 ;
     RECT  34.524 21.347 34.905 21.389 ;
     RECT  35.676 21.347 40.305 21.389 ;
     RECT  13.215 21.191 19.854 21.425 ;
     RECT  20.916 21.389 21.69 21.425 ;
     RECT  22.536 21.389 24.462 21.425 ;
     RECT  29.415 21.389 30.762 21.425 ;
     RECT  35.676 21.389 38.646 21.425 ;
     RECT  25.236 21.389 25.686 21.437 ;
     RECT  26.64 21.389 28.278 21.437 ;
     RECT  29.415 21.425 30.546 21.437 ;
     RECT  3.636 21.263 3.654 21.461 ;
     RECT  5.184 21.389 5.202 21.461 ;
     RECT  7.815 21.389 8.37 21.461 ;
     RECT  10.368 21.227 10.386 21.461 ;
     RECT  13.215 21.425 18.705 21.461 ;
     RECT  21.672 21.425 21.69 21.461 ;
     RECT  22.824 21.425 24.462 21.461 ;
     RECT  25.236 21.437 25.254 21.461 ;
     RECT  26.64 21.437 27.882 21.461 ;
     RECT  30.528 21.437 30.546 21.461 ;
     RECT  32.472 21.389 32.49 21.461 ;
     RECT  34.632 21.389 34.905 21.461 ;
     RECT  36.468 21.425 38.646 21.461 ;
     RECT  13.215 21.461 17.766 21.497 ;
     RECT  24.015 21.461 24.462 21.533 ;
     RECT  22.824 21.461 22.842 21.569 ;
     RECT  36.504 21.461 38.646 21.581 ;
     RECT  2.415 21.347 2.505 21.617 ;
     RECT  7.815 21.461 7.905 21.617 ;
     RECT  13.215 21.497 17.73 21.617 ;
     RECT  18.504 21.461 18.705 21.617 ;
     RECT  24.015 21.533 24.105 21.617 ;
     RECT  29.415 21.437 29.505 21.617 ;
     RECT  34.815 21.461 34.905 21.617 ;
     RECT  39.78 21.389 40.305 21.617 ;
     RECT  18.504 21.617 18.522 21.659 ;
     RECT  19.836 21.425 19.854 21.659 ;
     RECT  26.784 21.461 27.882 21.659 ;
     RECT  13.896 21.617 17.73 22.253 ;
     RECT  36.504 21.581 38.538 22.397 ;
     RECT  13.896 22.253 16.326 22.781 ;
     RECT  36.504 22.397 38.502 22.781 ;
     RECT  14.148 22.781 16.326 22.829 ;
     RECT  36.504 22.781 38.466 22.829 ;
     RECT  37.08 22.829 38.466 22.925 ;
     RECT  15.48 22.829 16.326 23.501 ;
     RECT  17.208 22.253 17.73 23.597 ;
     RECT  38.448 22.925 38.466 23.597 ;
     RECT  14.616 22.829 14.634 23.645 ;
     RECT  15.588 23.501 16.326 23.645 ;
     RECT  17.208 23.597 17.226 23.645 ;
     RECT  37.08 22.925 37.674 23.645 ;
     RECT  39.78 21.617 39.798 23.645 ;
    LAYER M4 ;
     RECT  0.06 13.872 0.097 16.872 ;
     RECT  0.097 13.872 0.181 16.968 ;
     RECT  0.181 13.776 0.323 16.968 ;
     RECT  0.323 14.16 1.105 16.968 ;
     RECT  1.105 14.16 1.209 17.112 ;
     RECT  1.209 14.16 2.293 17.016 ;
     RECT  2.401 6.336 2.408 6.36 ;
     RECT  2.329 10.896 2.408 10.92 ;
     RECT  0.181 12.24 2.408 12.264 ;
     RECT  2.293 14.16 2.408 17.64 ;
     RECT  2.293 20.4 2.408 21.192 ;
     RECT  2.408 2.148 2.512 21.612 ;
     RECT  2.512 2.352 2.704 21.342 ;
     RECT  2.704 14.16 2.801 14.28 ;
     RECT  2.704 10.32 2.819 10.92 ;
     RECT  2.704 4.128 2.945 8.52 ;
     RECT  2.819 10.32 3.197 10.392 ;
     RECT  2.945 4.128 3.347 4.152 ;
     RECT  2.704 15.408 3.413 16.872 ;
     RECT  2.945 5.28 3.491 8.52 ;
     RECT  3.491 6.24 3.701 8.52 ;
     RECT  3.413 15.792 3.769 16.872 ;
     RECT  3.769 15.792 3.773 16.968 ;
     RECT  4.129 20.016 4.201 20.04 ;
     RECT  2.704 12 4.237 13.128 ;
     RECT  2.801 14.256 4.237 14.28 ;
     RECT  4.237 12 4.349 14.28 ;
     RECT  4.349 13.584 4.381 14.28 ;
     RECT  3.773 16.32 4.381 16.968 ;
     RECT  2.704 2.352 4.601 2.376 ;
     RECT  4.381 13.584 4.601 15.336 ;
     RECT  4.201 20.016 4.709 20.088 ;
     RECT  4.601 15.024 4.817 15.336 ;
     RECT  3.197 10.32 4.844 10.344 ;
     RECT  3.701 7.392 5.141 8.52 ;
     RECT  5.141 8.496 5.213 8.52 ;
     RECT  3.701 6.24 5.317 6.264 ;
     RECT  4.844 9.888 5.321 10.344 ;
     RECT  4.817 15.312 5.353 15.336 ;
     RECT  4.381 16.32 5.353 17.064 ;
     RECT  4.709 20.016 5.537 20.04 ;
     RECT  5.353 15.312 5.789 17.064 ;
     RECT  5.317 5.472 5.825 6.264 ;
     RECT  2.704 21.168 5.857 21.192 ;
     RECT  5.461 9.744 5.897 9.768 ;
     RECT  5.789 15.84 5.897 17.064 ;
     RECT  5.897 16.416 6.005 17.064 ;
     RECT  4.601 13.584 6.076 14.04 ;
     RECT  4.349 12 6.145 12.264 ;
     RECT  6.076 14.016 6.145 14.04 ;
     RECT  5.857 20.688 6.221 21.192 ;
     RECT  6.145 19.536 6.293 19.56 ;
     RECT  6.277 8.544 6.364 8.568 ;
     RECT  6.005 16.56 6.437 17.064 ;
     RECT  6.721 18.816 6.805 18.84 ;
     RECT  6.145 14.016 6.829 14.808 ;
     RECT  6.221 20.688 6.829 20.712 ;
     RECT  6.541 8.976 6.949 9 ;
     RECT  6.829 19.824 7.261 20.712 ;
     RECT  6.613 3.072 7.297 3.096 ;
     RECT  6.145 11.856 7.369 12.264 ;
     RECT  5.825 6.24 7.669 6.264 ;
     RECT  5.141 7.392 7.669 7.464 ;
     RECT  6.949 8.976 7.669 9.48 ;
     RECT  7.009 10.752 7.669 10.776 ;
     RECT  7.369 11.856 7.669 12.552 ;
     RECT  6.829 14.016 7.729 15.048 ;
     RECT  7.297 2.88 7.808 3.096 ;
     RECT  6.937 4.512 7.808 4.68 ;
     RECT  7.669 6.24 7.808 7.464 ;
     RECT  7.669 8.976 7.808 12.552 ;
     RECT  7.729 13.872 7.808 15.048 ;
     RECT  6.437 16.56 7.808 16.584 ;
     RECT  7.153 18.72 7.808 18.744 ;
     RECT  7.261 19.824 7.808 21.144 ;
     RECT  7.808 2.148 7.912 21.612 ;
     RECT  7.912 2.418 8.104 21.342 ;
     RECT  8.104 20.448 8.201 21.144 ;
     RECT  8.104 10.08 8.237 10.92 ;
     RECT  8.104 12.24 8.243 15.192 ;
     RECT  8.237 10.176 8.273 10.92 ;
     RECT  8.243 13.872 8.417 15.192 ;
     RECT  8.104 5.856 8.489 7.416 ;
     RECT  8.104 2.736 8.561 4.728 ;
     RECT  8.201 20.448 8.561 20.472 ;
     RECT  8.104 18.72 8.597 18.744 ;
     RECT  8.489 6.384 8.633 7.416 ;
     RECT  8.633 6.624 8.849 7.416 ;
     RECT  8.561 2.736 8.921 3.432 ;
     RECT  8.849 6.672 8.921 7.416 ;
     RECT  8.561 4.56 9.065 4.728 ;
     RECT  8.104 8.976 9.097 9.096 ;
     RECT  9.097 8.832 9.173 9.096 ;
     RECT  9.173 8.832 9.209 9 ;
     RECT  8.104 16.56 9.241 16.632 ;
     RECT  8.273 10.176 9.457 10.2 ;
     RECT  8.417 14.832 9.601 15.192 ;
     RECT  9.241 16.464 9.601 16.632 ;
     RECT  9.601 14.832 9.605 16.632 ;
     RECT  8.243 12.24 9.673 12.504 ;
     RECT  9.133 19.488 9.713 19.512 ;
     RECT  9.421 4.992 9.785 5.016 ;
     RECT  9.605 15.984 9.857 16.632 ;
     RECT  8.921 2.832 9.925 3.432 ;
     RECT  8.921 7.392 9.971 7.416 ;
     RECT  9.457 10.176 9.997 10.968 ;
     RECT  9.925 17.472 10.037 17.832 ;
     RECT  9.709 13.68 10.325 13.704 ;
     RECT  9.997 10.176 10.393 11.208 ;
     RECT  10.393 10.08 10.541 11.208 ;
     RECT  10.541 10.08 10.613 10.2 ;
     RECT  9.673 12.24 10.789 12.6 ;
     RECT  10.573 20.112 10.789 20.136 ;
     RECT  10.541 11.184 10.825 11.208 ;
     RECT  10.789 12.24 10.825 13.656 ;
     RECT  10.825 11.184 10.829 13.656 ;
     RECT  10.825 7.776 10.837 7.8 ;
     RECT  9.209 8.976 10.837 9 ;
     RECT  10.829 12.144 10.873 13.656 ;
     RECT  10.837 7.776 10.909 9 ;
     RECT  10.789 6.384 10.933 6.408 ;
     RECT  10.909 8.496 10.973 9 ;
     RECT  9.857 15.984 11.009 16.488 ;
     RECT  10.933 6.384 11.113 6.456 ;
     RECT  11.009 15.984 11.117 16.056 ;
     RECT  9.605 14.832 11.149 14.856 ;
     RECT  11.005 18.768 11.185 18.792 ;
     RECT  10.789 19.824 11.185 20.136 ;
     RECT  11.149 14.832 11.189 15.432 ;
     RECT  10.037 17.472 11.365 17.64 ;
     RECT  11.185 18.768 11.365 20.76 ;
     RECT  11.365 17.472 11.369 20.76 ;
     RECT  11.369 19.824 11.441 20.76 ;
     RECT  10.873 13.632 11.477 13.656 ;
     RECT  11.441 20.736 11.549 20.76 ;
     RECT  10.537 4.416 11.693 4.44 ;
     RECT  11.189 15.408 11.837 15.432 ;
     RECT  10.873 12.144 11.941 12.504 ;
     RECT  11.941 11.376 11.987 12.504 ;
     RECT  11.113 6.048 12.193 6.456 ;
     RECT  12.121 15.504 12.301 16.152 ;
     RECT  11.369 17.472 12.301 18.792 ;
     RECT  9.925 2.592 12.421 3.432 ;
     RECT  11.987 11.376 12.697 12.264 ;
     RECT  12.697 11.232 12.733 12.264 ;
     RECT  12.421 2.592 12.805 3.672 ;
     RECT  12.301 15.504 12.805 18.792 ;
     RECT  10.973 8.496 12.949 8.52 ;
     RECT  11.005 9.552 12.949 9.576 ;
     RECT  12.949 8.496 12.985 9.576 ;
     RECT  12.733 10.608 12.985 12.264 ;
     RECT  12.985 8.496 13.093 12.264 ;
     RECT  12.553 13.584 13.093 13.608 ;
     RECT  12.805 2.352 13.208 3.672 ;
     RECT  12.193 5.76 13.208 6.456 ;
     RECT  13.093 8.496 13.208 13.608 ;
     RECT  12.805 14.784 13.208 18.792 ;
     RECT  13.208 2.148 13.312 21.612 ;
     RECT  13.312 2.352 13.504 21.612 ;
     RECT  13.504 16.656 13.619 19.032 ;
     RECT  13.504 7.296 13.709 14.952 ;
     RECT  13.709 9.312 13.781 14.952 ;
     RECT  13.504 2.352 13.817 5.16 ;
     RECT  13.619 16.848 13.853 19.032 ;
     RECT  13.781 10.608 13.925 14.952 ;
     RECT  13.885 22.752 14.029 22.776 ;
     RECT  14.029 21.648 14.098 22.776 ;
     RECT  13.925 10.8 14.285 14.952 ;
     RECT  14.285 10.848 14.321 14.952 ;
     RECT  14.098 21.648 14.524 22.824 ;
     RECT  14.524 22.8 14.533 22.824 ;
     RECT  14.321 10.848 14.537 13.608 ;
     RECT  14.497 6.288 14.569 6.312 ;
     RECT  13.709 7.296 14.569 8.232 ;
     RECT  14.321 14.688 14.605 14.952 ;
     RECT  13.817 3.216 14.629 5.16 ;
     RECT  14.524 21.648 14.629 21.672 ;
     RECT  14.629 3.216 14.641 5.256 ;
     RECT  14.569 6.288 14.641 8.232 ;
     RECT  14.641 3.216 14.675 8.232 ;
     RECT  13.781 9.312 14.689 9.576 ;
     RECT  14.537 10.848 14.789 13.128 ;
     RECT  14.675 3.216 14.825 7.992 ;
     RECT  14.605 14.688 14.825 15.384 ;
     RECT  13.853 16.848 14.861 18.696 ;
     RECT  14.629 21.552 14.905 21.672 ;
     RECT  14.905 21.552 14.969 21.624 ;
     RECT  14.969 21.552 15.109 21.576 ;
     RECT  15.109 21.12 15.196 21.576 ;
     RECT  14.929 0.096 15.289 0.12 ;
     RECT  15.289 0.096 15.372 0.6 ;
     RECT  14.789 11.136 15.401 13.128 ;
     RECT  14.825 3.648 15.473 7.992 ;
     RECT  15.401 11.136 15.473 12.84 ;
     RECT  15.372 0.096 15.481 0.648 ;
     RECT  14.825 15.072 15.541 15.384 ;
     RECT  15.469 19.872 15.577 19.896 ;
     RECT  15.577 19.872 15.578 19.944 ;
     RECT  15.473 6.432 15.581 7.992 ;
     RECT  15.469 1.728 15.685 1.752 ;
     RECT  14.533 22.8 15.937 23.64 ;
     RECT  14.861 16.848 16.009 18.456 ;
     RECT  15.581 6.768 16.013 7.992 ;
     RECT  15.541 15.072 16.045 15.576 ;
     RECT  16.009 16.848 16.045 18.84 ;
     RECT  15.473 3.648 16.049 5.304 ;
     RECT  16.013 6.816 16.117 7.992 ;
     RECT  15.937 22.704 16.211 23.64 ;
     RECT  14.689 9.552 16.213 9.576 ;
     RECT  15.473 11.136 16.213 11.256 ;
     RECT  16.213 9.552 16.259 11.256 ;
     RECT  16.259 10.416 16.3 11.256 ;
     RECT  15.196 21.552 16.369 21.576 ;
     RECT  16.045 15.072 16.405 18.84 ;
     RECT  15.685 1.728 16.441 1.8 ;
     RECT  16.369 21.12 16.499 21.576 ;
     RECT  16.441 1.728 16.517 1.848 ;
     RECT  16.517 1.824 16.525 1.848 ;
     RECT  16.117 6.816 16.553 8.52 ;
     RECT  15.473 12.336 16.589 12.84 ;
     RECT  16.499 21.552 16.613 21.576 ;
     RECT  16.049 3.648 16.729 5.16 ;
     RECT  16.613 21.552 16.741 21.672 ;
     RECT  16.741 21.552 16.877 22.248 ;
     RECT  15.578 19.92 16.949 19.944 ;
     RECT  16.553 6.816 17.053 7.992 ;
     RECT  17.053 6.576 17.077 7.992 ;
     RECT  16.877 21.552 17.093 21.576 ;
     RECT  15.481 0.096 17.129 0.552 ;
     RECT  17.077 6.288 17.129 7.992 ;
     RECT  17.129 6.288 17.164 7.656 ;
     RECT  16.211 23.568 17.237 23.64 ;
     RECT  16.405 14.928 17.521 18.84 ;
     RECT  16.3 11.088 17.653 11.256 ;
     RECT  16.589 12.336 17.653 12.6 ;
     RECT  17.237 23.568 17.741 23.592 ;
     RECT  16.729 2.736 17.845 5.16 ;
     RECT  17.129 0.48 17.849 0.552 ;
     RECT  16.765 8.976 17.917 9.192 ;
     RECT  17.849 0.528 17.993 0.552 ;
     RECT  17.845 2.688 18.169 5.16 ;
     RECT  17.164 6.576 18.169 7.656 ;
     RECT  18.169 2.688 18.205 7.656 ;
     RECT  17.917 8.976 18.205 10.008 ;
     RECT  18.205 2.688 18.608 10.008 ;
     RECT  17.653 11.088 18.608 12.6 ;
     RECT  17.521 14.928 18.608 19.656 ;
     RECT  18.608 2.148 18.712 21.612 ;
     RECT  18.712 2.418 18.904 21.342 ;
     RECT  18.904 16.368 18.965 17.208 ;
     RECT  18.904 3.312 19.001 8.232 ;
     RECT  19.001 3.36 19.043 8.232 ;
     RECT  19.043 3.696 19.109 6.12 ;
     RECT  18.965 16.368 19.109 16.584 ;
     RECT  19.109 3.696 19.427 6.072 ;
     RECT  18.904 18.24 19.469 18.264 ;
     RECT  18.904 13.632 19.916 13.656 ;
     RECT  19.427 3.696 19.973 5.784 ;
     RECT  19.916 13.632 20.003 14.52 ;
     RECT  20.077 19.056 20.189 19.08 ;
     RECT  18.904 11.376 20.245 12.456 ;
     RECT  20.245 10.56 20.261 12.456 ;
     RECT  20.261 10.56 20.333 12.36 ;
     RECT  19.109 16.56 20.365 16.584 ;
     RECT  20.245 8.304 20.581 8.328 ;
     RECT  19.973 3.696 20.693 5.208 ;
     RECT  20.333 10.8 20.837 12.36 ;
     RECT  20.365 16.464 20.909 16.584 ;
     RECT  20.581 7.392 20.941 8.328 ;
     RECT  18.904 9.504 20.941 9.576 ;
     RECT  20.837 10.8 20.989 12.312 ;
     RECT  20.941 7.392 21.017 9.576 ;
     RECT  20.909 16.56 21.049 16.584 ;
     RECT  20.693 3.696 21.089 4.536 ;
     RECT  21.049 16.56 21.125 17.208 ;
     RECT  21.089 4.224 21.305 4.536 ;
     RECT  21.017 8.256 21.341 9.576 ;
     RECT  20.761 6.288 21.445 6.312 ;
     RECT  20.989 10.8 21.529 11.928 ;
     RECT  21.445 6.288 21.589 7.224 ;
     RECT  21.341 9.552 21.683 9.576 ;
     RECT  21.265 18.768 21.701 18.792 ;
     RECT  21.341 8.256 21.737 8.28 ;
     RECT  21.305 4.464 21.881 4.536 ;
     RECT  21.589 5.568 21.913 7.224 ;
     RECT  21.125 17.184 21.913 17.208 ;
     RECT  21.913 5.184 21.98 7.224 ;
     RECT  21.98 5.184 22.067 7.656 ;
     RECT  21.529 11.904 22.093 11.928 ;
     RECT  20.003 13.632 22.093 13.656 ;
     RECT  21.913 17.184 22.093 17.496 ;
     RECT  22.093 11.904 22.165 13.656 ;
     RECT  22.165 11.904 22.211 14.376 ;
     RECT  21.529 10.8 22.405 10.92 ;
     RECT  22.405 10.368 22.465 10.92 ;
     RECT  22.067 5.184 22.529 6.312 ;
     RECT  21.805 2.352 22.669 2.376 ;
     RECT  22.093 17.184 22.769 17.688 ;
     RECT  22.769 17.04 22.853 17.688 ;
     RECT  22.669 2.352 22.921 2.856 ;
     RECT  22.211 11.904 22.921 12.888 ;
     RECT  22.529 6.288 22.961 6.312 ;
     RECT  22.529 5.184 23.029 5.256 ;
     RECT  22.525 19.632 23.029 19.656 ;
     RECT  22.465 10.368 23.173 10.392 ;
     RECT  22.853 17.472 23.389 17.688 ;
     RECT  23.029 5.136 24.001 5.256 ;
     RECT  23.317 6.816 24.001 6.84 ;
     RECT  22.921 2.352 24.008 3.048 ;
     RECT  24.001 5.136 24.008 6.84 ;
     RECT  23.173 8.544 24.008 8.568 ;
     RECT  23.173 9.744 24.008 10.392 ;
     RECT  22.921 11.76 24.008 12.888 ;
     RECT  22.211 14.352 24.008 14.376 ;
     RECT  23.101 15.456 24.008 15.48 ;
     RECT  23.389 17.472 24.008 17.784 ;
     RECT  23.029 19.536 24.008 19.656 ;
     RECT  22.525 21.264 24.008 21.288 ;
     RECT  24.008 2.148 24.112 21.612 ;
     RECT  24.112 2.418 24.304 21.342 ;
     RECT  24.304 15.456 24.419 16.392 ;
     RECT  24.304 19.536 24.509 19.56 ;
     RECT  24.304 2.736 24.515 2.856 ;
     RECT  24.304 4.512 24.517 6.84 ;
     RECT  24.419 15.456 24.689 15.96 ;
     RECT  24.517 5.712 24.941 6.84 ;
     RECT  24.515 2.736 25.013 2.76 ;
     RECT  24.941 5.712 25.265 5.88 ;
     RECT  24.304 11.904 25.333 12.264 ;
     RECT  25.265 5.856 25.379 5.88 ;
     RECT  24.689 15.696 25.379 15.96 ;
     RECT  25.297 19.968 25.381 19.992 ;
     RECT  24.304 17.952 25.513 18.168 ;
     RECT  24.304 21.216 25.657 21.24 ;
     RECT  25.657 21.216 25.697 21.432 ;
     RECT  24.304 9.936 25.765 9.96 ;
     RECT  25.333 11.136 25.765 12.264 ;
     RECT  25.765 9.936 25.801 12.264 ;
     RECT  25.801 9.936 25.805 13.032 ;
     RECT  25.805 9.936 25.849 11.928 ;
     RECT  24.517 4.512 25.949 4.68 ;
     RECT  25.513 17.616 26.161 18.168 ;
     RECT  26.161 17.088 26.197 18.168 ;
     RECT  24.304 8.544 26.201 8.568 ;
     RECT  26.197 17.04 26.273 18.168 ;
     RECT  26.273 17.04 26.284 17.976 ;
     RECT  25.949 4.656 26.453 4.68 ;
     RECT  25.849 9.936 26.741 9.96 ;
     RECT  25.379 15.936 26.741 15.96 ;
     RECT  25.805 13.008 27.025 13.032 ;
     RECT  26.485 14.16 27.025 14.184 ;
     RECT  26.284 17.088 27.065 17.976 ;
     RECT  25.849 11.136 27.301 11.928 ;
     RECT  27.025 13.008 27.301 14.184 ;
     RECT  27.301 11.136 27.347 14.184 ;
     RECT  25.909 6.096 27.421 6.12 ;
     RECT  27.385 2.736 27.565 2.76 ;
     RECT  27.421 6.096 27.673 6.168 ;
     RECT  27.673 6.096 27.817 6.984 ;
     RECT  27.817 6.096 27.923 7.416 ;
     RECT  27.565 2.352 27.929 2.76 ;
     RECT  27.923 6.672 28.217 7.416 ;
     RECT  27.347 11.136 28.321 13.032 ;
     RECT  28.177 19.872 28.429 19.896 ;
     RECT  28.321 10.32 28.861 13.032 ;
     RECT  27.347 14.16 28.861 14.184 ;
     RECT  27.929 2.352 29.408 2.376 ;
     RECT  29.269 3.936 29.408 3.96 ;
     RECT  28.213 5.568 29.408 5.592 ;
     RECT  28.217 6.672 29.408 6.696 ;
     RECT  28.861 10.32 29.408 14.184 ;
     RECT  28.933 15.264 29.408 15.288 ;
     RECT  27.065 17.088 29.408 17.736 ;
     RECT  28.429 19.296 29.408 19.896 ;
     RECT  25.697 21.408 29.408 21.432 ;
     RECT  29.408 2.148 29.512 21.612 ;
     RECT  29.512 2.352 29.549 21.432 ;
     RECT  29.549 2.418 29.704 21.432 ;
     RECT  29.704 19.296 30.131 21.432 ;
     RECT  30.131 19.296 30.172 20.712 ;
     RECT  29.704 6.096 30.197 6.696 ;
     RECT  29.704 15.264 30.485 15.288 ;
     RECT  29.704 17.088 30.611 18.024 ;
     RECT  29.704 12.528 30.665 14.184 ;
     RECT  30.172 19.296 30.953 19.32 ;
     RECT  29.704 2.544 31.021 2.568 ;
     RECT  29.704 11.184 31.097 11.208 ;
     RECT  30.172 20.688 31.169 20.712 ;
     RECT  30.197 6.096 31.241 6.12 ;
     RECT  29.704 7.92 31.285 7.944 ;
     RECT  31.285 7.248 31.372 7.944 ;
     RECT  31.021 4.944 31.421 4.968 ;
     RECT  30.665 12.528 31.529 13.08 ;
     RECT  31.525 4.416 31.745 4.44 ;
     RECT  31.021 2.496 31.765 2.568 ;
     RECT  31.765 2.496 31.813 3.048 ;
     RECT  31.813 2.496 31.853 3.96 ;
     RECT  30.611 18 31.916 18.024 ;
     RECT  31.273 19.056 31.964 19.08 ;
     RECT  31.916 17.04 32.005 18.024 ;
     RECT  31.964 19.056 32.005 19.656 ;
     RECT  31.372 7.92 32.029 7.944 ;
     RECT  31.957 15.792 32.041 15.816 ;
     RECT  32.005 17.04 32.051 19.656 ;
     RECT  32.029 7.92 32.141 7.992 ;
     RECT  32.141 7.968 32.465 7.992 ;
     RECT  32.065 9.888 32.537 9.912 ;
     RECT  32.051 18.72 32.573 19.08 ;
     RECT  31.853 2.496 32.825 2.52 ;
     RECT  32.573 19.056 32.861 19.08 ;
     RECT  30.665 14.16 33.001 14.184 ;
     RECT  31.529 13.008 33.073 13.08 ;
     RECT  32.533 4.944 33.109 4.968 ;
     RECT  33.073 12.864 33.301 13.08 ;
     RECT  33.001 14.16 33.301 14.232 ;
     RECT  32.051 17.04 33.325 17.064 ;
     RECT  33.325 17.04 33.365 17.16 ;
     RECT  33.289 15.408 33.373 15.432 ;
     RECT  33.301 12.864 33.437 14.232 ;
     RECT  33.437 12.864 33.469 12.888 ;
     RECT  31.853 3.936 33.649 3.96 ;
     RECT  33.469 12.768 33.653 12.888 ;
     RECT  33.437 14.16 33.761 14.232 ;
     RECT  32.713 6.768 33.973 6.792 ;
     RECT  32.281 11.664 34.069 11.688 ;
     RECT  33.649 3.84 34.153 3.96 ;
     RECT  34.153 3.408 34.261 3.96 ;
     RECT  33.109 4.944 34.261 5.016 ;
     RECT  34.081 18.816 34.693 18.84 ;
     RECT  34.261 3.408 34.808 5.016 ;
     RECT  33.973 6.768 34.808 6.888 ;
     RECT  33.937 8.448 34.808 8.472 ;
     RECT  34.069 9.6 34.808 11.688 ;
     RECT  33.653 12.864 34.808 12.888 ;
     RECT  33.761 14.16 34.808 14.184 ;
     RECT  33.365 17.136 34.808 17.16 ;
     RECT  34.693 18.768 34.808 18.84 ;
     RECT  31.669 21.12 34.808 21.144 ;
     RECT  34.808 2.148 34.912 21.612 ;
     RECT  34.912 2.418 35.104 21.342 ;
     RECT  35.104 6.24 35.165 8.52 ;
     RECT  35.104 18.768 35.273 18.792 ;
     RECT  35.104 19.92 35.363 20.616 ;
     RECT  35.104 4.944 35.597 5.064 ;
     RECT  35.597 4.944 35.669 4.968 ;
     RECT  35.165 7.392 36.065 8.52 ;
     RECT  35.104 15.84 36.133 15.96 ;
     RECT  35.363 19.92 36.137 19.944 ;
     RECT  36.065 8.496 36.188 8.52 ;
     RECT  36.065 7.392 36.245 7.416 ;
     RECT  35.104 2.88 36.275 3.864 ;
     RECT  36.188 8.496 36.275 8.904 ;
     RECT  35.104 10.08 36.421 10.104 ;
     RECT  35.104 17.616 36.421 17.64 ;
     RECT  36.275 8.496 36.461 8.52 ;
     RECT  36.421 9.696 36.461 10.104 ;
     RECT  36.097 18.816 36.467 18.84 ;
     RECT  36.133 15.84 36.517 16.44 ;
     RECT  35.104 12.768 36.529 12.888 ;
     RECT  36.517 15.312 36.673 16.44 ;
     RECT  36.493 22.8 36.701 22.824 ;
     RECT  36.529 12.768 36.857 13.032 ;
     RECT  36.701 22.176 36.901 22.824 ;
     RECT  36.673 14.928 36.925 16.44 ;
     RECT  36.421 17.424 36.925 17.64 ;
     RECT  36.925 14.928 36.949 17.64 ;
     RECT  36.949 14.928 37.036 18.168 ;
     RECT  36.461 9.696 37.073 9.72 ;
     RECT  36.817 19.632 37.177 19.656 ;
     RECT  37.036 14.928 37.645 17.544 ;
     RECT  37.645 14.832 37.721 17.544 ;
     RECT  35.165 6.24 37.793 6.264 ;
     RECT  37.721 14.832 37.793 15.096 ;
     RECT  36.857 12.768 37.825 12.84 ;
     RECT  37.721 16.56 37.865 17.544 ;
     RECT  36.275 2.88 37.957 2.904 ;
     RECT  37.681 5.136 38.003 5.16 ;
     RECT  37.957 2.88 38.044 3.432 ;
     RECT  36.901 22.176 38.108 23.64 ;
     RECT  38.108 21.312 38.195 23.64 ;
     RECT  37.825 12.768 38.197 13.32 ;
     RECT  38.197 12.768 38.243 13.8 ;
     RECT  37.177 19.632 38.257 19.848 ;
     RECT  38.243 13.776 38.284 13.8 ;
     RECT  38.257 19.632 38.297 19.944 ;
     RECT  37.933 7.632 38.369 7.656 ;
     RECT  38.195 21.552 38.513 23.64 ;
     RECT  38.513 21.552 38.549 22.392 ;
     RECT  38.437 10.944 38.585 10.968 ;
     RECT  38.549 21.552 38.657 21.576 ;
     RECT  38.297 19.92 38.797 19.944 ;
     RECT  37.793 15.024 38.833 15.096 ;
     RECT  38.797 19.92 38.837 20.568 ;
     RECT  38.797 10.368 38.909 10.392 ;
     RECT  38.044 3.408 39.161 3.432 ;
     RECT  38.545 17.616 39.445 17.64 ;
     RECT  38.761 18.672 39.445 18.696 ;
     RECT  37.865 16.56 39.548 16.584 ;
     RECT  39.445 17.616 39.548 18.696 ;
     RECT  39.548 16.56 39.589 18.696 ;
     RECT  37.393 9.024 39.596 9.048 ;
     RECT  38.837 20.544 39.805 20.568 ;
     RECT  38.513 23.616 39.809 23.64 ;
     RECT  39.589 16.512 40.057 18.696 ;
     RECT  38.797 6.816 40.208 6.84 ;
     RECT  39.381 7.92 40.208 7.944 ;
     RECT  39.596 9.024 40.208 9.96 ;
     RECT  39.625 11.424 40.208 11.448 ;
     RECT  38.243 12.768 40.208 12.792 ;
     RECT  38.833 14.832 40.208 15.096 ;
     RECT  40.057 16.512 40.208 19.368 ;
     RECT  39.805 20.544 40.208 20.712 ;
     RECT  40.208 2.148 40.312 21.612 ;
     RECT  40.312 2.418 40.504 21.342 ;
    LAYER M5 ;
     RECT  15.312 0.016 17.064 0.515 ;
     RECT  15.312 0.515 16.968 0.563 ;
     RECT  15.312 0.563 16.488 0.611 ;
     RECT  15.408 0.611 16.488 0.659 ;
     RECT  15.696 0.659 16.488 1.763 ;
     RECT  15.792 1.763 16.488 1.811 ;
     RECT  16.368 1.811 16.488 1.859 ;
     RECT  2.4 2.137 2.52 2.151 ;
     RECT  7.8 2.137 7.92 2.151 ;
     RECT  13.2 2.137 13.32 2.151 ;
     RECT  18.6 2.137 18.72 2.151 ;
     RECT  24 2.137 24.12 2.151 ;
     RECT  29.4 2.137 29.52 2.151 ;
     RECT  34.8 2.137 34.92 2.151 ;
     RECT  40.2 2.137 40.32 2.151 ;
     RECT  2.4 2.151 2.712 2.341 ;
     RECT  29.4 2.151 29.712 2.341 ;
     RECT  13.2 2.151 13.512 2.581 ;
     RECT  7.8 2.151 8.112 2.725 ;
     RECT  24 2.151 24.312 2.725 ;
     RECT  9.936 2.581 9.96 2.821 ;
     RECT  31.776 2.485 31.8 3.059 ;
     RECT  12.432 2.581 13.512 3.205 ;
     RECT  18.6 2.151 18.912 3.349 ;
     RECT  7.8 2.725 8.904 3.443 ;
     RECT  9.936 2.821 10.488 3.443 ;
     RECT  16.368 1.859 16.392 3.637 ;
     RECT  12.432 3.205 14.232 3.683 ;
     RECT  34.8 2.151 35.112 3.925 ;
     RECT  2.4 2.341 3.336 4.163 ;
     RECT  7.8 3.443 8.112 4.501 ;
     RECT  13.2 3.683 14.232 4.501 ;
     RECT  13.2 4.501 14.664 4.595 ;
     RECT  34.272 3.925 35.112 4.691 ;
     RECT  16.368 3.637 17.112 5.171 ;
     RECT  37.968 2.869 37.992 5.171 ;
     RECT  2.4 4.163 2.712 5.269 ;
     RECT  18.6 3.349 19.032 5.269 ;
     RECT  29.28 2.341 29.712 5.603 ;
     RECT  24 2.725 24.504 5.845 ;
     RECT  18.6 5.269 19.416 6.083 ;
     RECT  34.8 4.691 35.112 6.229 ;
     RECT  36.24 3.829 36.264 6.229 ;
     RECT  16.8 5.171 17.112 6.323 ;
     RECT  34.8 6.229 36.264 6.757 ;
     RECT  18.6 6.083 19.032 6.805 ;
     RECT  40.2 2.151 40.512 6.805 ;
     RECT  2.4 5.269 3.48 6.851 ;
     RECT  33.984 6.757 36.264 6.899 ;
     RECT  27.888 6.133 27.912 6.995 ;
     RECT  14.64 4.595 14.664 7.333 ;
     RECT  2.4 6.851 3.384 7.427 ;
     RECT  34.08 6.899 36.264 7.427 ;
     RECT  6.96 4.501 8.112 7.429 ;
     RECT  18.24 6.805 19.032 7.619 ;
     RECT  22.032 6.277 22.056 7.667 ;
     RECT  9.936 3.443 9.96 7.765 ;
     RECT  31.296 7.237 31.32 7.955 ;
     RECT  39.408 6.805 40.512 7.955 ;
     RECT  14.64 7.333 15.432 8.003 ;
     RECT  13.2 4.595 13.512 8.485 ;
     RECT  9.936 7.765 10.872 8.531 ;
     RECT  6.288 7.429 8.112 8.579 ;
     RECT  24 5.845 25.368 8.579 ;
     RECT  14.64 8.003 14.664 9.347 ;
     RECT  6.96 8.579 8.112 9.491 ;
     RECT  16.8 6.323 16.824 9.541 ;
     RECT  18.384 7.619 19.032 9.587 ;
     RECT  21.648 8.245 21.672 9.587 ;
     RECT  25.344 8.579 25.368 9.925 ;
     RECT  18.384 9.587 18.912 10.019 ;
     RECT  29.4 5.603 29.712 10.309 ;
     RECT  4.896 7.957 4.92 10.355 ;
     RECT  2.4 7.427 2.712 10.357 ;
     RECT  20.256 8.293 20.28 10.595 ;
     RECT  22.416 10.357 22.44 10.789 ;
     RECT  25.344 9.925 25.8 10.883 ;
     RECT  2.4 10.357 2.808 10.931 ;
     RECT  21.456 10.789 22.44 10.931 ;
     RECT  16.224 9.541 16.824 11.123 ;
     RECT  11.424 9.541 11.448 11.365 ;
     RECT  21.456 10.931 21.48 11.365 ;
     RECT  20.928 11.365 21.48 11.459 ;
     RECT  39.648 7.955 40.512 11.459 ;
     RECT  16.704 11.123 16.824 11.509 ;
     RECT  18.6 10.019 18.912 11.509 ;
     RECT  28.464 10.309 29.712 11.699 ;
     RECT  34.08 7.427 35.112 11.699 ;
     RECT  13.2 8.485 13.656 11.941 ;
     RECT  11.424 11.365 11.976 12.179 ;
     RECT  20.928 11.459 20.952 12.323 ;
     RECT  11.952 12.179 11.976 12.515 ;
     RECT  16.704 11.509 18.912 12.611 ;
     RECT  13.104 11.941 13.656 12.851 ;
     RECT  36.24 7.427 36.264 12.853 ;
     RECT  29.04 11.699 29.712 12.899 ;
     RECT  36.144 12.853 36.264 12.899 ;
     RECT  7.392 9.491 8.112 13.045 ;
     RECT  9.936 8.531 9.96 13.045 ;
     RECT  27.312 11.653 27.336 13.331 ;
     RECT  13.2 12.851 13.656 13.525 ;
     RECT  6 11.989 6.024 13.619 ;
     RECT  0.192 12.229 0.216 13.765 ;
     RECT  0.192 13.765 0.312 13.811 ;
     RECT  38.208 12.757 38.232 13.811 ;
     RECT  7.392 13.045 8.232 13.859 ;
     RECT  7.392 13.859 8.112 14.005 ;
     RECT  6.768 14.005 8.112 14.051 ;
     RECT  13.2 13.525 14.28 14.051 ;
     RECT  22.176 13.621 22.2 14.387 ;
     RECT  9.936 13.045 10.824 14.867 ;
     RECT  36.144 12.899 36.168 15.301 ;
     RECT  33.312 13.669 33.336 15.443 ;
     RECT  24 8.579 24.312 15.445 ;
     RECT  25.344 10.883 25.368 15.445 ;
     RECT  0.288 13.811 0.312 15.733 ;
     RECT  0.192 15.733 0.312 15.923 ;
     RECT  24 15.445 25.368 15.925 ;
     RECT  36.144 15.301 36.552 15.971 ;
     RECT  0.288 15.923 0.312 16.211 ;
     RECT  24 15.925 26.232 16.403 ;
     RECT  36.144 15.971 36.456 16.451 ;
     RECT  40.2 11.459 40.512 16.501 ;
     RECT  19.968 14.485 19.992 16.595 ;
     RECT  2.4 10.931 2.712 16.645 ;
     RECT  13.2 14.051 13.656 16.645 ;
     RECT  25.344 16.403 26.232 17.075 ;
     RECT  31.968 15.781 31.992 17.075 ;
     RECT  29.4 12.899 29.712 17.077 ;
     RECT  1.152 16.981 1.176 17.123 ;
     RECT  39.6 16.501 40.512 17.411 ;
     RECT  36.432 16.451 36.456 17.413 ;
     RECT  22.8 17.029 22.824 17.507 ;
     RECT  16.704 12.611 16.728 17.605 ;
     RECT  2.304 16.645 2.712 17.651 ;
     RECT  9.936 14.867 9.96 17.843 ;
     RECT  16.512 17.605 16.728 17.939 ;
     RECT  16.56 17.939 16.728 17.941 ;
     RECT  18.6 12.611 18.912 17.941 ;
     RECT  13.104 16.645 13.656 18.035 ;
     RECT  29.4 17.077 30.6 18.035 ;
     RECT  24 16.403 24.312 18.133 ;
     RECT  25.344 17.075 25.368 18.133 ;
     RECT  36.432 17.413 36.984 18.179 ;
     RECT  13.2 18.035 13.656 18.227 ;
     RECT  13.2 18.227 13.608 18.371 ;
     RECT  6.768 14.051 6.792 18.851 ;
     RECT  16.56 17.941 18.912 18.851 ;
     RECT  36.432 18.179 36.456 18.851 ;
     RECT  17.664 18.851 18.912 19.043 ;
     RECT  24 18.133 25.368 19.571 ;
     RECT  7.8 14.051 8.112 19.813 ;
     RECT  34.8 11.699 35.112 19.909 ;
     RECT  25.344 19.571 25.368 20.003 ;
     RECT  29.4 18.035 29.712 20.149 ;
     RECT  2.4 17.651 2.712 20.389 ;
     RECT  34.8 19.909 35.352 20.627 ;
     RECT  6.864 19.813 8.112 20.723 ;
     RECT  15.504 19.861 15.528 21.109 ;
     RECT  16.56 18.851 16.584 21.109 ;
     RECT  32.016 17.989 32.04 21.155 ;
     RECT  2.304 20.389 2.712 21.203 ;
     RECT  29.4 20.149 30.12 21.443 ;
     RECT  15.12 21.109 16.584 21.541 ;
     RECT  38.16 21.301 38.184 21.541 ;
     RECT  2.4 21.203 2.712 21.609 ;
     RECT  7.8 20.723 8.112 21.609 ;
     RECT  18.6 19.043 18.912 21.609 ;
     RECT  24 19.571 24.312 21.609 ;
     RECT  29.4 21.443 29.712 21.609 ;
     RECT  34.8 20.627 35.112 21.609 ;
     RECT  40.2 17.411 40.512 21.609 ;
     RECT  2.4 21.609 2.52 21.623 ;
     RECT  7.8 21.609 7.92 21.623 ;
     RECT  13.2 18.371 13.512 21.623 ;
     RECT  18.6 21.609 18.72 21.623 ;
     RECT  24 21.609 24.12 21.623 ;
     RECT  29.4 21.609 29.52 21.623 ;
     RECT  34.8 21.609 34.92 21.623 ;
     RECT  40.2 21.609 40.32 21.623 ;
     RECT  14.64 21.541 16.968 21.637 ;
     RECT  38.16 21.541 38.568 22.165 ;
     RECT  14.16 21.637 16.968 22.741 ;
     RECT  14.064 22.741 16.968 23.557 ;
     RECT  14.064 23.557 17.064 23.696 ;
     RECT  36.72 22.165 38.568 23.696 ;
     RECT  8.904 2.725 9.936 3.443 ;
     RECT  17.112 3.637 18.6 6.323 ;
     RECT  35.112 3.829 36.24 6.229 ;
     RECT  2.712 4.163 3.336 5.269 ;
     RECT  13.512 4.595 14.64 8.485 ;
     RECT  29.28 5.603 29.4 6.133 ;
     RECT  27.912 6.133 29.4 6.995 ;
     RECT  16.824 6.323 18.6 6.805 ;
     RECT  16.824 6.805 18.24 7.619 ;
     RECT  15.432 7.333 16.8 8.003 ;
     RECT  35.112 7.427 36.24 12.853 ;
     RECT  4.92 7.957 6.288 8.579 ;
     RECT  19.032 8.293 20.256 9.587 ;
     RECT  20.28 8.293 21.648 9.587 ;
     RECT  13.656 8.485 14.64 9.347 ;
     RECT  9.96 8.531 10.872 9.541 ;
     RECT  24.312 8.579 25.344 15.445 ;
     RECT  9.96 9.541 11.424 12.179 ;
     RECT  18.912 9.587 20.256 10.595 ;
     RECT  20.28 9.587 21.672 10.357 ;
     RECT  18.384 10.019 18.6 11.509 ;
     RECT  20.28 10.357 22.416 10.595 ;
     RECT  20.928 10.595 22.416 10.789 ;
     RECT  20.928 10.789 21.456 11.365 ;
     RECT  11.976 11.365 13.2 11.941 ;
     RECT  27.336 11.653 28.464 11.699 ;
     RECT  11.976 11.941 13.104 12.515 ;
     RECT  6.024 11.989 7.392 13.619 ;
     RECT  9.96 12.179 11.952 12.515 ;
     RECT  9.96 12.515 10.824 13.045 ;
     RECT  35.112 12.853 36.144 16.451 ;
     RECT  6.768 13.619 7.392 14.005 ;
     RECT  33.336 13.669 34.8 15.443 ;
     RECT  6.792 14.051 7.8 18.851 ;
     RECT  18.912 14.485 19.968 16.595 ;
     RECT  36.456 15.971 36.552 17.413 ;
     RECT  24.312 16.403 25.344 18.133 ;
     RECT  35.112 16.451 36.432 18.851 ;
     RECT  1.176 16.981 2.304 17.123 ;
     RECT  22.824 17.029 24 17.507 ;
     RECT  31.968 17.075 31.992 17.077 ;
     RECT  30.6 17.077 31.992 17.989 ;
     RECT  30.6 17.989 32.016 18.035 ;
     RECT  6.864 18.851 7.8 19.813 ;
     RECT  16.584 18.851 17.664 19.043 ;
     RECT  35.112 18.851 35.352 19.909 ;
     RECT  24.312 19.571 25.344 20.003 ;
     RECT  15.528 19.861 16.56 21.109 ;
     RECT  13.512 21.541 14.64 21.623 ;
     RECT  14.064 21.623 14.64 21.637 ;
     RECT  14.064 21.637 14.16 22.741 ;
  END
END ot_qkvd_ke_ctl
END LIBRARY
